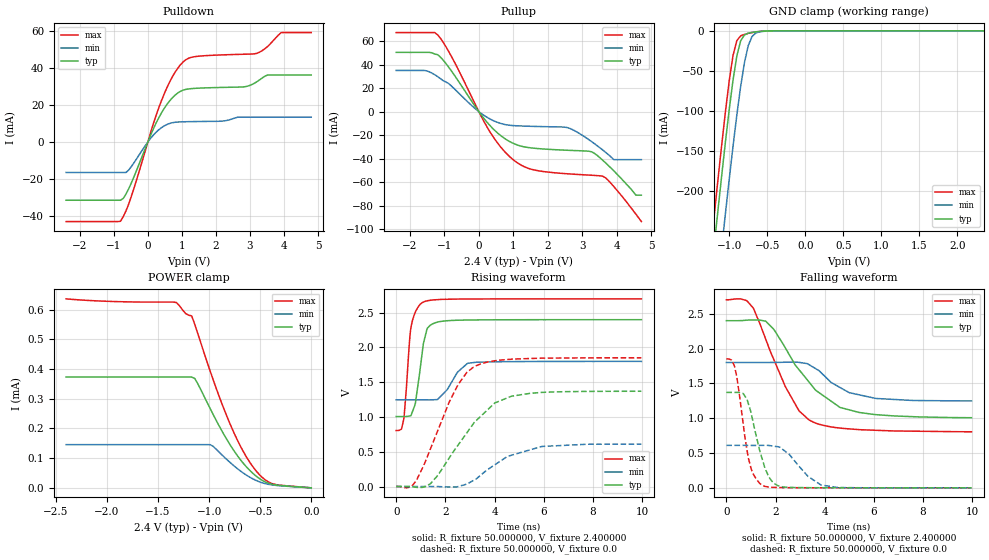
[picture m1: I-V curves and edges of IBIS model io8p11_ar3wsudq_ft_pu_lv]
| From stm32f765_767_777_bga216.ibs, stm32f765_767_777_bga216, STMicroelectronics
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|   Model io8p11_ar3wsudq_ft_pu_lv
[Model]  io8p11_ar3wsudq_ft_pu_lv
Model_type I/O
Polarity   Non-Inverting
Enable   Active-Low
Vinl =   0.720000V
Vinh =   1.680000V
Vmeas =  1.200000V
Cref =   30.000000pF
Rref =   100.000000M
Vref =   0.0V
C_comp   3.740800pF   3.684200pF   3.822900pF
[Temperature Range]   25.000000   0.125000k   -40.000000
[Pullup Reference]   2.400000V   1.800000V   2.700000V
[Pulldown Reference]   0.0V   0.0V   0.0V
[POWER Clamp Reference]   2.400000V   1.800000V   2.700000V
[GND Clamp Reference]   0.0V   0.0V   0.0V
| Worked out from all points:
|   slope of the pulldown table from 0 to 0.36 V, typ, clamps not added: 25 ohm
|   slope of the pullup table from 0 to 0.36 V, typ, clamps not added: 27.7 ohm
|   GND clamp passes 1 mA (typ) near -0.62 V on its own axis
|   rising waveform, R_fixture 50.000000, V_fixture 2.400000: 20-80 % time 336ps typ, 658ps min, 256ps max; typ from 1.01 V to 2.4 V
|   rising waveform, R_fixture 50.000000, V_fixture 0.0: 20-80 % time 1.79ns typ, 1.76ns min, 1.35ns max; typ from 0.001 V to 1.37 V
|   falling waveform, R_fixture 50.000000, V_fixture 2.400000: 20-80 % time 1.89ns typ, 1.38ns min, 1.43ns max; typ from 2.4 V to 1.01 V
|   falling waveform, R_fixture 50.000000, V_fixture 0.0: 20-80 % time 589ps typ, 969ps min, 465ps max; typ from 1.37 V to 0.001 V
[Pulldown]
|Voltage   I(typ)   I(min)   I(max)
-2.4V     -31.47mA   -16.45mA   -43.01mA
-800mV    -31.47mA   -16.45mA   -42.85mA
-480mV    -21.98mA   -13.17mA   -29.21mA
80mV      3.63mA     1.966mA    5.014mA
480mV     18.16mA    8.738mA    26.02mA
800mV     25.38mA    10.72mA    37.77mA
1.12V     28.53mA    11.02mA    44.6mA
2.8V      29.84mA    13.47mA    47.53mA
3.2V      32.6mA     13.47mA    48.03mA
3.52V     36.29mA    13.47mA    51.75mA
3.92V     36.29mA    13.47mA    59.26mA
4.8V      36.29mA    13.47mA    59.26mA
[Pullup]
|Voltage   I(typ)   I(min)   I(max)
-2.4V     50.45mA    35.08mA    67.3mA
-1.52V    50.45mA    34.74mA    67.3mA
-1.2V     48.51mA    29.88mA    65.47mA
320mV     -11.75mA   -6.207mA   -17.08mA
1.04V     -27.53mA   -11.97mA   -41.91mA
1.6V      -31.13mA   -12.57mA   -49.63mA
2.56V     -32.88mA   -13.52mA   -52.9mA
3.28V     -34.25mA   -25.63mA   -54.17mA
3.6V      -41.44mA   -32.74mA   -55.02mA
3.92V     -50.46mA   -40.9mA    -63.78mA
4.56V     -71.1mA    -40.9mA    -87.25mA
4.72V     -71.1mA    -40.9mA    -93.6mA
[GND_clamp]
|Voltage   I(typ)   I(min)   I(max)
-2.4V     -1.429A    -1.514A    -1.399A
-1.25V    -315.9mA   -407.2mA   -278.2mA
-1.2V     -270.1mA   -361.3mA   -232.1mA
-1.15V    -225mA     -316mA     -186.8mA
-1.1V     -180.9mA   -271.3mA   -142.7mA
-1.05V    -138.2mA   -227.5mA   -100.5mA
-950mV    -61.14mA   -143.6mA   -30.43mA
-900mV    -31.23mA   -104.7mA   -12.14mA
-850mV    -12.49mA   -69.4mA    -6.221mA
-750mV    -2.898mA   -18.35mA   -3.18mA
-600mV    -750.2uA   -1.218mA   -738.3uA
2.35V     0A         0A         0A
[POWER_clamp]
|Voltage   I(typ)   I(min)   I(max)
-2.4V     373.1uA    145.5uA    636.5uA
-1.32V    373.1uA    145.5uA    624.2uA
-1.23V    373.1uA    145.5uA    587.2uA
-1.17V    373.1uA    145.5uA    579uA
-1.14V    368.3uA    145.5uA    550.7uA
-990mV    267.3uA    145.5uA    393.9uA
-810mV    153.6uA    90.29uA    227.7uA
-690mV    93.37uA    55.97uA    138.2uA
-570mV    48.37uA    29.94uA    70.44uA
-480mV    25.27uA    17.04uA    35.17uA
-390mV    12.49uA    10.18uA    15.16uA
0V        0A         0A         0A
[Ramp]
| variable   typ   min   max
dV/dt_r  0.82171/1.78935n   0.36414/1.75080n   1.11083/1.34732n
dV/dt_f  0.83244/1.88685n   0.33204/1.39338n   1.13509/1.42724n
R_load = 50.000000
[Rising Waveform]
R_fixture= 50.000000
V_fixture= 2.400000
V_fixture_min= 1.800000
V_fixture_max= 2.700000
|time   V(typ)   V(min)   V(max)
0s        1.007V     1.247V     805.8mV
220.2ps   1.007V     1.247V     830.9mV
320.3ps   1.007V     1.247V     1.003V
600.6ps   1.021V     1.247V     2.286V
780.8ps   1.2V       1.247V     2.51V
1.081ns   1.991V     1.247V     2.649V
1.381ns   2.319V     1.246V     2.679V
1.682ns   2.366V     1.253V     2.688V
2.903ns   2.395V     1.773V     2.697V
9.97ns    2.4V       1.8V       2.699V
[Rising Waveform]
R_fixture= 50.000000
V_fixture= 0.0
V_fixture_min= 0.0
V_fixture_max= 0.0
|time   V(typ)   V(min)   V(max)
0s        1.045mV    904.9uV    1.196mV
540.5ps   -429uV     891.3uV    -9.362mV
820.8ps   -10.65mV   901.6uV    87.51mV
1.401ns   44.05mV    974.9uV    550.7mV
2.182ns   425.9mV    -5.745mV   1.234V
3.143ns   906.8mV    88.13mV    1.717V
4.004ns   1.2V       311.9mV    1.809V
4.705ns   1.3V       452mV      1.832V
5.926ns   1.354V     576.7mV    1.847V
9.97ns    1.371V     610.1mV    1.852V
[Falling Waveform]
R_fixture= 50.000000
V_fixture= 2.400000
V_fixture_min= 1.800000
V_fixture_max= 2.700000
|time   V(typ)   V(min)   V(max)
0s        2.4V       1.8V       2.699V
820.8ps   2.407V     1.8V       2.689V
1.101ns   2.41V      1.8V       2.578V
1.602ns   2.393V     1.8V       2.134V
2.402ns   2.008V     1.804V     1.452V
2.963ns   1.694V     1.801V     1.104V
3.363ns   1.519V     1.768V     974.8mV
4.625ns   1.155V     1.441V     858.8mV
5.385ns   1.084V     1.337V     836.6mV
9.97ns    1.007V     1.247V     805.8mV
[Falling Waveform]
R_fixture= 50.000000
V_fixture= 0.0
V_fixture_min= 0.0
V_fixture_max= 0.0
|time   V(typ)   V(min)   V(max)
0s        1.371V     610.1mV    1.852V
340.3ps   1.371V     610.2mV    1.735V
440.4ps   1.371V     610.1mV    1.561V
840.8ps   1.268V     610mV      544.1mV
1.081ns   956.2mV    609.9mV    211.8mV
1.441ns   435.5mV    610.3mV    41.05mV
1.722ns   164mV      609.2mV    12.69mV
2.042ns   42.27mV    593.5mV    6.276mV
3.864ns   2.605mV    41.07mV    2.005mV
9.97ns    1.045mV    904.9uV    1.196mV
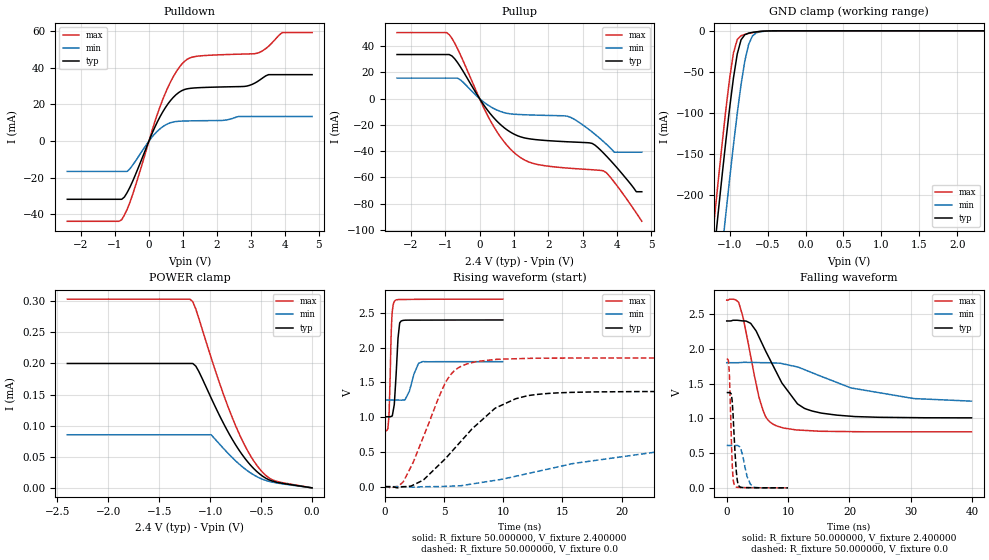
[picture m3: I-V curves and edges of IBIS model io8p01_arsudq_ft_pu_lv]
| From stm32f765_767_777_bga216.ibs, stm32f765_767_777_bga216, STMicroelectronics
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|   Model io8p01_arsudq_ft_pu_lv
[Model]  io8p01_arsudq_ft_pu_lv
Model_type I/O
Polarity   Non-Inverting
Enable   Active-Low
Vinl =   0.720000V
Vinh =   1.680000V
Vmeas =  1.200000V
Cref =   50.000000pF
Rref =   100.000000M
Vref =   0.0V
C_comp   2.239000pF   2.178700pF   2.334000pF
[Temperature Range]   25.000000   0.125000k   -40.000000
[Pullup Reference]   2.400000V   1.800000V   2.700000V
[Pulldown Reference]   0.0V   0.0V   0.0V
[POWER Clamp Reference]   2.400000V   1.800000V   2.700000V
[GND Clamp Reference]   0.0V   0.0V   0.0V
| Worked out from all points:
|   slope of the pulldown table from 0 to 0.36 V, typ, clamps not added: 25 ohm
|   slope of the pullup table from 0 to 0.36 V, typ, clamps not added: 27.7 ohm
|   GND clamp passes 1 mA (typ) near -0.62 V on its own axis
|   rising waveform, R_fixture 50.000000, V_fixture 2.400000: 20-80 % time 273ps typ, 607ps min, 182ps max; typ from 1.01 V to 2.4 V
|   rising waveform, R_fixture 50.000000, V_fixture 0.0: 20-80 % time 4.76ns typ, 12.1ns min, 2.63ns max; typ from 0.001 V to 1.37 V
|   falling waveform, R_fixture 50.000000, V_fixture 2.400000: 20-80 % time 5.35ns typ, 12.6ns min, 2.71ns max; typ from 2.4 V to 1.01 V
|   falling waveform, R_fixture 50.000000, V_fixture 0.0: 20-80 % time 525ps typ, 977ps min, 384ps max; typ from 1.37 V to 0.001 V
[Pulldown]
|Voltage   I(typ)   I(min)   I(max)
-2.4V     -31.73mA   -16.51mA   -43.74mA
-800mV    -31.73mA   -16.51mA   -42.87mA
-480mV    -21.98mA   -13.17mA   -29.21mA
80mV      3.63mA     1.966mA    5.014mA
480mV     18.16mA    8.738mA    26.02mA
800mV     25.38mA    10.72mA    37.77mA
1.12V     28.53mA    11.02mA    44.6mA
2.8V      29.84mA    13.46mA    47.53mA
3.2V      32.6mA     13.46mA    48.03mA
3.52V     36.28mA    13.46mA    51.75mA
3.92V     36.28mA    13.46mA    59.24mA
4.8V      36.28mA    13.46mA    59.24mA
[Pullup]
|Voltage   I(typ)   I(min)   I(max)
-2.4V     33.5mA     15.55mA    50.22mA
-960mV    33.5mA     15.55mA    50.22mA
-560mV    24.27mA    14.29mA    33.52mA
320mV     -11.75mA   -6.207mA   -17.08mA
960mV     -26.47mA   -11.82mA   -40.02mA
1.52V     -30.88mA   -12.51mA   -49.05mA
2.56V     -32.88mA   -13.48mA   -52.9mA
3.28V     -34.18mA   -25.52mA   -54.17mA
3.6V      -41.3mA    -32.61mA   -54.97mA
3.92V     -50.32mA   -40.8mA    -63.62mA
4.56V     -70.9mA    -40.8mA    -87.07mA
4.72V     -70.9mA    -40.8mA    -93.4mA
[GND_clamp]
|Voltage   I(typ)   I(min)   I(max)
-2.4V     -1.424A    -1.508A    -1.393A
-1.25V    -311.2mA   -401.9mA   -273.3mA
-1.2V     -265.4mA   -356.1mA   -227.2mA
-1.15V    -220.4mA   -310.8mA   -181.9mA
-1.1V     -176.3mA   -266.2mA   -137.9mA
-1.05V    -133.8mA   -222.5mA   -95.87mA
-950mV    -57.3mA    -138.9mA   -26.98mA
-900mV    -28.27mA   -100.4mA   -10.59mA
-850mV    -11.01mA   -65.54mA   -5.958mA
-750mV    -2.834mA   -16.5mA    -3.178mA
-600mV    -750uA     -1.164mA   -738.3uA
2.35V     0A         0A         0A
[POWER_clamp]
|Voltage   I(typ)   I(min)   I(max)
-2.4V     200uA      85.39uA    303.5uA
-1.2V     200uA      85.39uA    303.5uA
-1.17V    200uA      85.39uA    299.5uA
-1.14V    195.7uA    85.39uA    287.5uA
-990mV    144.6uA    85.39uA    209.3uA
-870mV    104.1uA    63.61uA    150.8uA
-780mV    77.28uA    48.2uA     111.8uA
-660mV    47.71uA    30.75uA    68.21uA
-570mV    30.64uA    20.61uA    42.79uA
-480mV    18.19uA    13.44uA    24.07uA
-390mV    10.91uA    9.231uA    13.01uA
0V        0A         0A         0A
[Ramp]
| variable   typ   min   max
dV/dt_r  0.82207/4.75460n   0.38473/13.01194n   1.11065/2.62062n
dV/dt_f  0.83604/5.35818n   0.32310/13.42769n   1.13692/2.70885n
R_load = 50.000000
[Rising Waveform]
R_fixture= 50.000000
V_fixture= 2.400000
V_fixture_min= 1.800000
V_fixture_max= 2.700000
|time   V(typ)   V(min)   V(max)
0s        1.007V     1.247V     805.7mV
260.3ps   1.007V     1.247V     832.2mV
340.3ps   1.007V     1.247V     990mV
600.6ps   1.016V     1.247V     2.443V
860.9ps   1.342V     1.247V     2.677V
1.121ns   2.143V     1.247V     2.693V
1.381ns   2.384V     1.246V     2.695V
1.722ns   2.396V     1.255V     2.695V
3.203ns   2.398V     1.8V       2.697V
9.97ns    2.4V       1.8V       2.7V
[Rising Waveform]
R_fixture= 50.000000
V_fixture= 0.0
V_fixture_min= 0.0
V_fixture_max= 0.0
|time   V(typ)   V(min)   V(max)
0s        1.058mV    913.6uV    1.356mV
1.602ns   195.2uV    739uV      81.86mV
3.283ns   100mV      1.235mV    727.7mV
5.125ns   405.2mV    5.225mV    1.498V
5.846ns   542.4mV    10.29mV    1.664V
6.967ns   755.7mV    29.06mV    1.768V
9.369ns   1.134V     93.43mV    1.832V
12.97ns   1.33V      223.3mV    1.85V
24.82ns   1.37V      544.4mV    1.853V
39.88ns   1.371V     610.2mV    1.853V
[Falling Waveform]
R_fixture= 50.000000
V_fixture= 2.400000
V_fixture_min= 1.800000
V_fixture_max= 2.700000
|time   V(typ)   V(min)   V(max)
0s        2.4V       1.8V       2.7V
2.002ns   2.407V     1.801V     2.653V
3.924ns   2.363V     1.805V     1.883V
5.285ns   2.164V     1.801V     1.294V
6.326ns   1.97V      1.8V       1.026V
7.608ns   1.747V     1.797V     913.5mV
11.53ns   1.208V     1.739V     832.8mV
13.93ns   1.105V     1.655V     820.9mV
20.26ns   1.03V      1.437V     809.2mV
39.88ns   1.007V     1.247V     805.7mV
[Falling Waveform]
R_fixture= 50.000000
V_fixture= 0.0
V_fixture_min= 0.0
V_fixture_max= 0.0
|time   V(typ)   V(min)   V(max)
0s        1.371V     610.2mV    1.853V
380.4ps   1.371V     610.2mV    1.721V
480.5ps   1.371V     610.2mV    1.522V
740.7ps   1.347V     610.1mV    729.9mV
981ps     1.129V     609.8mV    201.4mV
1.281ns   622.6mV    609.6mV    34.21mV
1.702ns   121.2mV    611.7mV    8.928mV
2.062ns   20.48mV    594.6mV    6.466mV
3.864ns   3.478mV    54mV       3.254mV
9.97ns    1.058mV    913.6uV    1.356mV
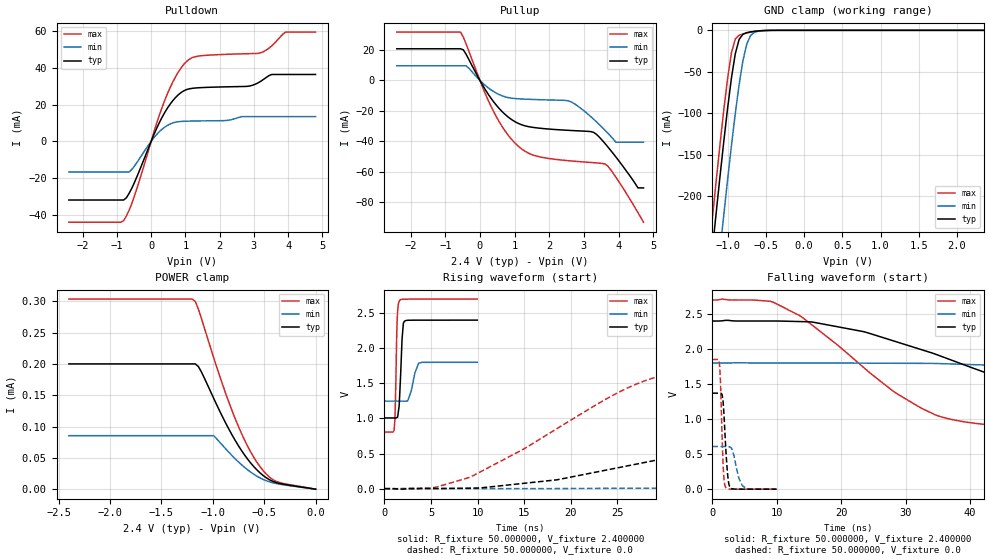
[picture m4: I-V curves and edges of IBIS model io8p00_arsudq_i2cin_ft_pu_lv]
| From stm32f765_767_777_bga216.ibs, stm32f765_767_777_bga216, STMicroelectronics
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|   Model io8p00_arsudq_i2cin_ft_pu_lv
[Model]  io8p00_arsudq_i2cin_ft_pu_lv
Model_type I/O
Polarity   Non-Inverting
Enable   Active-Low
Vinl =   0.720000V
Vinh =   1.680000V
Vmeas =  1.200000V
Cref =   50.000000pF
Rref =   100.000000M
Vref =   0.0V
C_comp   2.226900pF   2.174000pF   2.332300pF
[Temperature Range]   25.000000   0.125000k   -40.000000
[Pullup Reference]   2.400000V   1.800000V   2.700000V
[Pulldown Reference]   0.0V   0.0V   0.0V
[POWER Clamp Reference]   2.400000V   1.800000V   2.700000V
[GND Clamp Reference]   0.0V   0.0V   0.0V
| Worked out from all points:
|   slope of the pulldown table from 0 to 0.36 V, typ, clamps not added: 25 ohm
|   slope of the pullup table from 0 to 0.36 V, typ, clamps not added: 27.7 ohm
|   GND clamp passes 1 mA (typ) near -0.62 V on its own axis
|   rising waveform, R_fixture 50.000000, V_fixture 2.400000: 20-80 % time 270ps typ, 604ps min, 183ps max; typ from 1.01 V to 2.4 V
|   rising waveform, R_fixture 50.000000, V_fixture 0.0: 20-80 % time 32.4ns typ, 81.1ns min, 14.8ns max; typ from 0.001 V to 1.37 V
|   falling waveform, R_fixture 50.000000, V_fixture 2.400000: 20-80 % time 29.1ns typ, 74.5ns min, 16.1ns max; typ from 2.4 V to 1.01 V
|   falling waveform, R_fixture 50.000000, V_fixture 0.0: 20-80 % time 523ps typ, 973ps min, 382ps max; typ from 1.37 V to 0.001 V
[Pulldown]
|Voltage   I(typ)   I(min)   I(max)
-2.4V     -31.73mA   -16.51mA   -43.74mA
-800mV    -31.73mA   -16.51mA   -42.87mA
-480mV    -21.98mA   -13.17mA   -29.21mA
80mV      3.63mA     1.966mA    5.014mA
480mV     18.16mA    8.738mA    26.02mA
800mV     25.38mA    10.72mA    37.77mA
1.12V     28.53mA    11.02mA    44.6mA
2.8V      29.84mA    13.46mA    47.53mA
3.2V      32.6mA     13.46mA    48.03mA
3.52V     36.28mA    13.46mA    51.75mA
3.92V     36.28mA    13.46mA    59.24mA
4.8V      36.28mA    13.46mA    59.24mA
[Pullup]
|Voltage   I(typ)   I(min)   I(max)
-2.4V     20.87mA    9.659mA    31.88mA
-560mV    20.87mA    9.659mA    31.88mA
-400mV    17.27mA    9.659mA    24.06mA
320mV     -11.75mA   -6.207mA   -17.08mA
960mV     -26.47mA   -11.82mA   -40.02mA
1.52V     -30.88mA   -12.51mA   -49.05mA
2.56V     -32.88mA   -13.48mA   -52.9mA
3.28V     -34.18mA   -25.51mA   -54.17mA
3.6V      -41.3mA    -32.61mA   -54.97mA
3.92V     -50.32mA   -40.7mA    -63.62mA
4.56V     -70.8mA    -40.7mA    -87.07mA
4.72V     -70.8mA    -40.7mA    -93.4mA
[GND_clamp]
|Voltage   I(typ)   I(min)   I(max)
-2.4V     -1.425A    -1.509A    -1.394A
-1.25V    -311.2mA   -401.9mA   -273.3mA
-1.2V     -265.4mA   -356.1mA   -227.2mA
-1.15V    -220.4mA   -310.8mA   -181.9mA
-1.1V     -176.3mA   -266.2mA   -137.9mA
-1.05V    -133.8mA   -222.5mA   -95.87mA
-950mV    -57.3mA    -138.9mA   -26.98mA
-900mV    -28.27mA   -100.4mA   -10.59mA
-850mV    -11.01mA   -65.54mA   -5.958mA
-750mV    -2.834mA   -16.5mA    -3.178mA
-600mV    -750uA     -1.164mA   -738.3uA
2.35V     0A         0A         0A
[POWER_clamp]
|Voltage   I(typ)   I(min)   I(max)
-2.4V     200uA      85.39uA    303.5uA
-1.2V     200uA      85.39uA    303.5uA
-1.17V    200uA      85.39uA    299.5uA
-1.14V    195.7uA    85.39uA    287.5uA
-990mV    144.6uA    85.39uA    209.3uA
-870mV    104.1uA    63.61uA    150.8uA
-780mV    77.28uA    48.2uA     111.8uA
-660mV    47.71uA    30.75uA    68.21uA
-570mV    30.64uA    20.61uA    42.79uA
-480mV    18.19uA    13.44uA    24.07uA
-390mV    10.91uA    9.231uA    13.01uA
0V        0A         0A         0A
[Ramp]
| variable   typ   min   max
dV/dt_r  0.82267/32.39155n   0.36219/82.87552n   1.11077/14.73368n
dV/dt_f  0.83628/29.16661n   0.32700/79.59643n   1.13704/16.12745n
R_load = 50.000000
[Rising Waveform]
R_fixture= 50.000000
V_fixture= 2.400000
V_fixture_min= 1.800000
V_fixture_max= 2.700000
|time   V(typ)   V(min)   V(max)
0s        1.007V     1.247V     805.7mV
1.041ns   1.007V     1.247V     840.2mV
1.141ns   1.007V     1.247V     1.06V
1.381ns   1.016V     1.247V     2.446V
1.642ns   1.345V     1.247V     2.681V
1.902ns   2.148V     1.247V     2.696V
2.162ns   2.386V     1.246V     2.698V
2.503ns   2.398V     1.253V     2.699V
3.664ns   2.4V       1.785V     2.7V
9.97ns    2.4V       1.8V       2.7V
[Rising Waveform]
R_fixture= 50.000000
V_fixture= 0.0
V_fixture_min= 0.0
V_fixture_max= 0.0
|time   V(typ)   V(min)   V(max)
0s        880.4uV    840.2uV    911.2uV
5.005ns   2.73mV     1.883mV    11.14mV
9.009ns   7.894mV    1.892mV    156mV
18.52ns   126.6mV    2.404mV    854.3mV
28.53ns   388.8mV    7.732mV    1.561V
39.04ns   690.7mV    31.5mV     1.769V
65.57ns   1.239V     123.7mV    1.844V
80.08ns   1.318V     195.9mV    1.849V
147.6ns   1.37V      493.3mV    1.852V
249.2ns   1.371V     610.3mV    1.852V
[Falling Waveform]
R_fixture= 50.000000
V_fixture= 2.400000
V_fixture_min= 1.800000
V_fixture_max= 2.700000
|time   V(typ)   V(min)   V(max)
0s        2.4V       1.8V       2.7V
9.51ns    2.4V       1.8V       2.666V
14.01ns   2.391V     1.8V       2.448V
23.52ns   2.248V     1.799V     1.734V
32.53ns   1.989V     1.796V     1.152V
44.54ns   1.597V     1.766V     906mV
60.56ns   1.236V     1.708V     844.3mV
85.59ns   1.079V     1.567V     816.3mV
123.6ns   1.028V     1.386V     807.5mV
249.2ns   1.007V     1.247V     805.7mV
[Falling Waveform]
R_fixture= 50.000000
V_fixture= 0.0
V_fixture_min= 0.0
V_fixture_max= 0.0
|time   V(typ)   V(min)   V(max)
0s        1.371V     610.3mV    1.852V
1.061ns   1.371V     610.2mV    1.82V
1.261ns   1.371V     610.2mV    1.521V
1.662ns   1.255V     610mV      358.8mV
1.842ns   998mV      609.7mV    112.1mV
2.062ns   616.6mV    609.5mV    29.21mV
2.482ns   116.6mV    611.8mV    3.313mV
2.843ns   17.53mV    594.5mV    1.377mV
4.645ns   915.7uV    51.91mV    955.9uV
9.97ns    880.4uV    840.2uV    911.2uV
